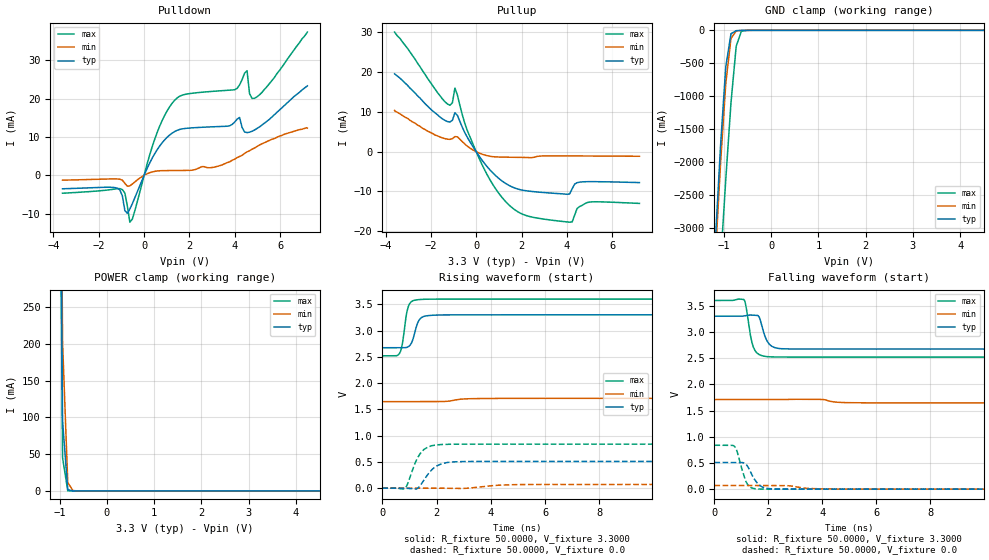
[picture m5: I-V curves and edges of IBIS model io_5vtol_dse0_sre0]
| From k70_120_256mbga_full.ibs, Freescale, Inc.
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[Model]  io_5vtol_dse0_sre0
|   Model io_5vtol_dse0_sre0
| Library cells for typ/min/max conditions are connected as defined below:
|  pad - External Pad
|  ipp_do - Core Input
|  ipp_obe - Output Buffer Enable
|  esd_boost - vdd_s_3v
|  esd_bus - vdd_s_3v
|  ipp_ame - vss_s_lv
|  ipp_dse - vss_s_lv
|  ipp_ina40a_5vtol - NC
|  ipp_ina40b_5vtol - NC
|  ipp_ina_5vtol - NC
|  ipp_ina_mux_3v - NC
|  ipp_ind - NC
|  ipp_ind_3v - NC
|  ipp_pue - vss_s_lv
|  ipp_sre - vss_s_lv
|  tie_3v - vdd_s_3v
|  tie_hi - vdd_s_lv
|  vbuf_3v - vdd_s_3v
|  vdd_bulk_lv - vdd_s_lv
|  vdd_s_3v - vdd_s_3v
|  vdd_s_lv - vdd_s_lv
|  vss_bulk - vss_s_3v
|  vss_s_3v - vss_s_3v
|  vss_s_lv - vss_s_lv
| All other pins connected to ground
Model_type I/O
Polarity   Non-Inverting
Enable   Active-High
Vinl =   1.1550V
Vinh =   2.3100V
Vmeas =  1.6500V
Cref =   25.0000pF
Rref =   50.0000
Vref =   0.0V
C_comp   2.8049pF   2.7887pF   2.9184pF
[Temperature Range]   25.0000   0.1250k   -40.0000
[Voltage Range]   3.3000V   1.7100V   3.6000V
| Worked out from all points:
|   slope of the pulldown table from 0 to 0.495 V, typ, clamps not added: 83.9 ohm
|   slope of the pullup table from 0 to 0.495 V, typ, clamps not added: 129 ohm
|   GND clamp passes 1 mA (typ) near -0.58 V on its own axis
|   POWER clamp passes 1 mA (typ) near -0.79 V on its own axis
|   rising waveform, R_fixture 50.0000, V_fixture 3.3000: 20-80 % time 227ps typ, 495ps min, 184ps max; typ from 2.67 V to 3.3 V
|   rising waveform, R_fixture 50.0000, V_fixture 0.0: 20-80 % time 495ps typ, 853ps min, 421ps max; typ from 0 V to 0.509 V
|   falling waveform, R_fixture 50.0000, V_fixture 3.3000: 20-80 % time 261ps typ, 395ps min, 224ps max; typ from 3.3 V to 2.67 V
|   falling waveform, R_fixture 50.0000, V_fixture 0.0: 20-80 % time 356ps typ, 598ps min, 285ps max; typ from 0.509 V to 0 V
[Pulldown]
|Voltage   I(typ)   I(min)   I(max)
-3.6V     -3.51mA    -1.26mA    -4.66mA
-1.29V    -3.199mA   -941uA     -3.563mA
-960mV    -5.372mA   -1.272mA   -3.734mA
-850mV    -9.168mA   -2.085mA   -4.602mA
-630mV    -8.788mA   -2.751mA   -12.21mA
580mV     6.709mA    1.133mA    11.22mA
1.35V     11.41mA    1.251mA    19.56mA
4.21V     15.06mA    4.9mA      23.54mA
4.54V     11.12mA    6.1mA      27.24mA
4.65V     11.23mA    6.4mA      21.29mA
4.87V     11.8mA     7.1mA      20.05mA
7.2V      23.3mA     12.3mA     37.3mA
[Pullup]
|Voltage   I(typ)   I(min)   I(max)
-3.6V     19.6mA     10.4mA     30.1mA
-1.38V    7.89mA     3.29mA     12.58mA
-1.05V    7.911mA    3.26mA     12.3mA
-940mV    9.791mA    3.808mA    16.02mA
-500mV    4.763mA    1.923mA    7.069mA
270mV     -2.225mA   -643.7uA   -3.408mA
930mV     -6.397mA   -1.322mA   -9.943mA
1.7V      -9.133mA   -1.405mA   -14.6mA
4.12V     -10.63mA   -1.06mA    -17.73mA
4.34V     -8.156mA   -1.06mA    -16mA
4.89V     -7.539mA   -1.08mA    -12.8mA
7.2V      -7.77mA    -1.14mA    -13mA
[GND_clamp]
|Voltage   I(typ)   I(min)   I(max)
-3.6V     -39.79A    -39.79A    -41.16A
-1.18V    -3.193A    -3.444A    -4.927A
-1.07V    -1.746A    -2.021A    -3.54A
-960mV    -554.7mA   -808.1mA   -2.265A
-850mV    -51.43mA   -125.2mA   -1.104A
-740mV    -5.185mA   -9.147mA   -242.4mA
-630mV    -1.474mA   -1.195mA   -14.98mA
-520mV    -384.8uA   -298.7uA   -1.148mA
7.2V      0A         0A         0A
[POWER_clamp]
|Voltage   I(typ)   I(min)   I(max)
-3.6V     45.62A     45.23A     45.93A
-1.05V    987.4mA    1.121A     927.4mA
-940mV    95.32mA    202.8mA    45.29mA
-830mV    1.645mA    11.46mA    218.1uA
-720mV    22.84uA    474.3uA    919.1nA
-610mV    316.6nA    19.24uA    4.178nA
7.2V      0A         0A         0A
[Ramp]
| variable   typ   min   max
dV/dt_r  0.3054/0.4951n   41.9957m/0.8527n   0.5027/0.4214n
dV/dt_f  0.3761/0.2609n   37.9284m/0.3951n   0.6484/0.2238n
R_load = 50.0000
[Rising Waveform]
R_fixture= 50.0000
V_fixture= 3.3000
V_fixture_min= 1.7100
V_fixture_max= 3.6000
|time   V(typ)   V(min)   V(max)
0s        2.673V     1.647V     2.519V
634.4ps   2.673V     1.647V     2.567V
742.6ps   2.673V     1.647V     2.76V
871.8ps   2.676V     1.647V     3.26V
943.5ps   2.689V     1.647V     3.438V
1.083ns   2.772V     1.647V     3.554V
1.335ns   3.181V     1.647V     3.59V
1.526ns   3.269V     1.647V     3.595V
2.19ns    3.298V     1.648V     3.599V
20ns      3.3V       1.71V      3.6V
[Rising Waveform]
R_fixture= 50.0000
V_fixture= 0.0
V_fixture_min= 0.0
V_fixture_max= 0.0
|time   V(typ)   V(min)   V(max)
0s        1.227nV    111.1nV    934.1pV
813ps     -20.38uV   2.027uV    -12.84mV
916.7ps   -3.205mV   -1.881uV   64.05mV
1.228ns   -19.69mV   8.868uV    500.1mV
1.393ns   47.23mV    76.41uV    657.8mV
1.746ns   307.5mV    269.6uV    794.2mV
2.14ns    453.5mV    -984uV     829.6mV
2.852ns   505.1mV    -7.746mV   836.7mV
5.06ns    508.7mV    67.63mV    837.4mV
20ns      508.9mV    69.99mV    837.8mV
[Falling Waveform]
R_fixture= 50.0000
V_fixture= 3.3000
V_fixture_min= 1.7100
V_fixture_max= 3.6000
|time   V(typ)   V(min)   V(max)
0s        3.3V       1.71V      3.6V
1.091ns   3.304V     1.71V      3.619V
1.155ns   3.31V      1.71V      3.527V
1.336ns   3.322V     1.71V      2.928V
1.438ns   3.32V      1.71V      2.716V
1.658ns   3.286V     1.71V      2.568V
1.946ns   2.83V      1.71V      2.529V
2.227ns   2.701V     1.71V      2.522V
2.633ns   2.677V     1.711V     2.521V
20ns      2.673V     1.647V     2.519V
[Falling Waveform]
R_fixture= 50.0000
V_fixture= 0.0
V_fixture_min= 0.0
V_fixture_max= 0.0
|time   V(typ)   V(min)   V(max)
0s        509mV      70.01mV    838mV
753.1ps   509mV      70.01mV    810.7mV
842ps     508.8mV    70.01mV    715.3mV
1.17ns    474.4mV    70mV       143.5mV
1.301ns   367.7mV    70mV       46.27mV
1.546ns   142.6mV    70mV       6.11mV
1.873ns   22.86mV    69.98mV    1.023mV
2.398ns   1.287mV    70.09mV    487.2uV
4.55ns    221.8uV    1.579mV    290.7uV
20ns      62.85uV    14.83uV    94.9uV
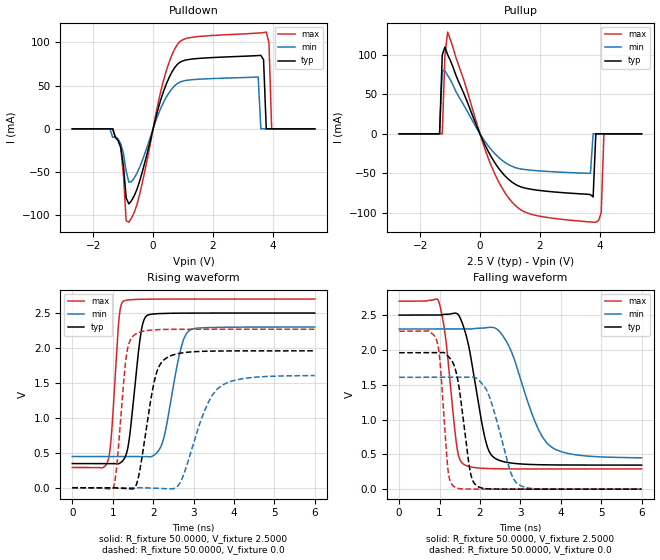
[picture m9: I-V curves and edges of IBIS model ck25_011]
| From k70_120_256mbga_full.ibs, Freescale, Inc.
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|   Model ck25_011
[Model]  ck25_011
Model_type Output
Polarity   Non-Inverting
Enable   Active-High
Vmeas =  1.2500V
Cref =   5.0000pF
Rref =   50.0000
C_comp   2.8000pF   2.5000pF   3.3000pF
[Temperature Range]   25.0000   0.1250k   -40.0000
[Voltage Range]   2.5000V   2.3000V   2.7000V
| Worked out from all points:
|   slope of the pulldown table from 0 to 0.375 V, typ, clamps not added: 8.18 ohm
|   slope of the pullup table from 0 to 0.375 V, typ, clamps not added: 12.9 ohm
|   rising waveform, R_fixture 50.0000, V_fixture 2.5000: 20-80 % time 236ps typ, 355ps min, 157ps max; typ from 0.346 V to 2.5 V
|   rising waveform, R_fixture 50.0000, V_fixture 0.0: 20-80 % time 334ps typ, 591ps min, 199ps max; typ from 0 V to 1.96 V
|   falling waveform, R_fixture 50.0000, V_fixture 2.5000: 20-80 % time 390ps typ, 673ps min, 252ps max; typ from 2.5 V to 0.346 V
|   falling waveform, R_fixture 50.0000, V_fixture 0.0: 20-80 % time 268ps typ, 459ps min, 168ps max; typ from 1.96 V to 0 V
[Pulldown]
|Voltage   I(typ)   I(min)   I(max)
-2.7V     0A         0A         0A
-1.35V    0A         -10mA      0A
-1.08V    -21.44mA   -17.23mA   -22.4mA
-810mV    -87.03mA   -61.88mA   -108.1mA
900mV     77.14mA    54.19mA    101.1mA
3.51V     84.84mA    60mA       110.9mA
3.6V      85mA       0A         111.1mA
3.69V     80mA       0A         111.4mA
3.78V     0A         0A         112mA
3.87V     0A         0A         100mA
3.96V     0A         0A         0A
5.4V      0A         0A         0A
[Pullup]
|Voltage   I(typ)   I(min)   I(max)
-2.7V     0A         0A         0A
-1.35V    0A         0A         0A
-1.26V    100mA      80mA       0A
-1.08V    100.4mA    74.2mA     129mA
1.44V     -68.08mA   -44.94mA   -97.96mA
3.69V     -77mA      -50mA      -111.7mA
3.78V     -80mA      0A         -112mA
3.87V     0A         0A         -112mA
3.96V     0A         0A         -110mA
4.05V     0A         0A         -100mA
4.14V     0A         0A         0A
5.4V      0A         0A         0A
[Ramp]
| variable   typ   min   max
dV/dt_r  1.1755/0.3339n   0.9631/0.5879n   1.3611/0.1989n
dV/dt_f  1.2925/0.3904n   1.1099/0.6692n   1.4460/0.2523n
R_load = 50.0000
[Rising Waveform]
R_fixture= 50.0000
V_fixture= 2.5000
V_fixture_min= 2.3000
V_fixture_max= 2.7000
|time   V(typ)   V(min)   V(max)
0s        345.9mV    446.9mV    289.9mV
885.9ps   345.8mV    446.9mV    390.1mV
1.154ns   345.3mV    446.9mV    2.407V
1.267ns   398.2mV    446.9mV    2.67V
1.405ns   677.7mV    446.9mV    2.689V
1.701ns   2.223V     446.9mV    2.697V
1.842ns   2.461V     446.4mV    2.698V
2.234ns   2.494V     652mV      2.7V
2.889ns   2.499V     2.248V     2.7V
6ns       2.5V       2.3V       2.7V
[Rising Waveform]
R_fixture= 50.0000
V_fixture= 0.0
|time   V(typ)   V(min)   V(max)
0s        3.819nV    263.8nV    1.818nV
1.021ns   292.5uV    252nV      11.35mV
1.341ns   -13.78mV   371.2nV    1.897V
1.571ns   25.49mV    -4.817uV   2.2V
2.035ns   1.538V     -6.959mV   2.26V
2.292ns   1.842V     -13.99mV   2.265V
2.657ns   1.924V     61.22mV    2.268V
3.284ns   1.953V     1.115V     2.268V
3.681ns   1.957V     1.456V     2.268V
6ns       1.959V     1.605V     2.268V
[Falling Waveform]
R_fixture= 50.0000
V_fixture= 2.5000
V_fixture_min= 2.3000
V_fixture_max= 2.7000
|time   V(typ)   V(min)   V(max)
0s        2.5V       2.3V       2.7V
976.9ps   2.5V       2.3V       2.699V
1.145ns   2.512V     2.3V       2.193V
1.436ns   2.521V     2.3V       576.7mV
1.591ns   2.337V     2.3V       359.2mV
2.107ns   775.2mV    2.316V     298.3mV
2.337ns   458.1mV    2.321V     293.7mV
2.722ns   379.2mV    2.046V     291mV
3.764ns   348.4mV    606mV      290mV
6ns       345.9mV    450.2mV    289.9mV
[Falling Waveform]
R_fixture= 50.0000
V_fixture= 0.0
|time   V(typ)   V(min)   V(max)
0s        1.959V     1.607V     2.268V
926.7ps   1.959V     1.607V     2.138V
1.013ns   1.959V     1.607V     1.817V
1.211ns   1.909V     1.607V     263.9mV
1.375ns   1.751V     1.607V     30.09mV
1.76ns    246.3mV    1.607V     1.635mV
1.938ns   41.96mV    1.582V     873.9uV
2.2ns     4.538mV    1.378V     347.6uV
2.965ns   505.8uV    62.98mV    24.95uV
6ns       457.6nV    38.86uV    9.273nV
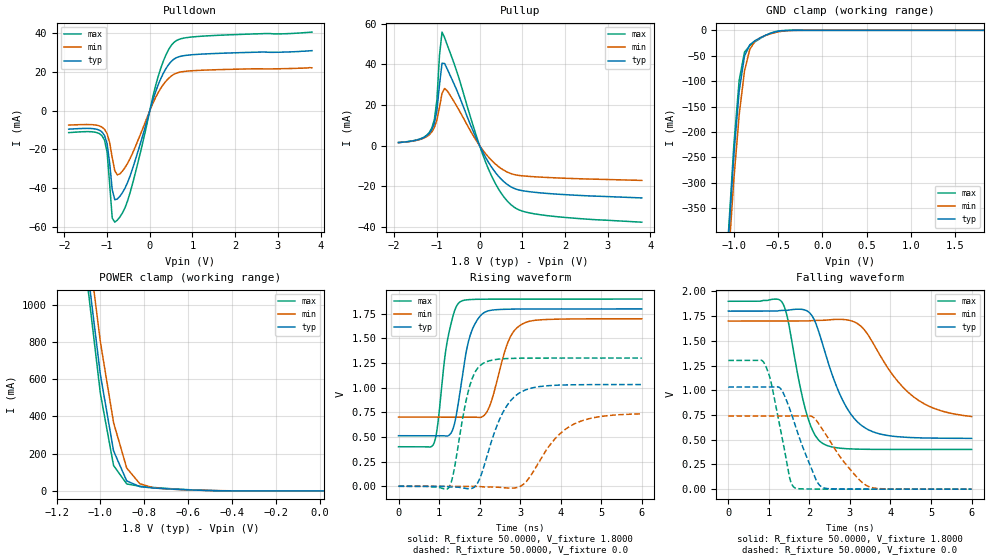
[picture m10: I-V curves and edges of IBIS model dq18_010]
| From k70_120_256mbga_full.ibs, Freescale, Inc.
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|   Model dq18_010
[Model]  dq18_010
Model_type 3-state
Polarity   Non-Inverting
Enable   Active-High
Vmeas =  0.9000V
Cref =   5.0000pF
Rref =   50.0000
C_comp   2.8000pF   2.5000pF   3.3000pF
[Temperature Range]   25.0000   0.1250k   -40.0000
[Voltage Range]   1.8000V   1.7000V   1.9000V
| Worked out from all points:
|   slope of the pulldown table from 0 to 0.27 V, typ, clamps not added: 15.7 ohm
|   slope of the pullup table from 0 to 0.27 V, typ, clamps not added: 26.3 ohm
|   GND clamp passes 1 mA (typ) near -0.46 V on its own axis
|   POWER clamp passes 1 mA (typ) near -0.45 V on its own axis
|   rising waveform, R_fixture 50.0000, V_fixture 1.8000: 20-80 % time 330ps typ, 419ps min, 277ps max; typ from 0.513 V to 1.8 V
|   rising waveform, R_fixture 50.0000, V_fixture 0.0: 20-80 % time 574ps typ, 828ps min, 362ps max; typ from 0 V to 1.03 V
|   falling waveform, R_fixture 50.0000, V_fixture 1.8000: 20-80 % time 732ps typ, 1.06ns min, 455ps max; typ from 1.8 V to 0.514 V
|   falling waveform, R_fixture 50.0000, V_fixture 0.0: 20-80 % time 548ps typ, 770ps min, 369ps max; typ from 1.03 V to 0 V
[Pulldown]
|Voltage   I(typ)   I(min)   I(max)
-1.9V     -9.546mA   -7.415mA   -11.34mA
-1.24V    -9.613mA   -7.507mA   -11.32mA
-1.06V    -12.84mA   -9.622mA   -15.29mA
-1V       -17.1mA    -11.9mA    -21.47mA
-880mV    -40.92mA   -24.25mA   -55.54mA
-820mV    -46.05mA   -31.1mA    -57.7mA
-700mV    -44.27mA   -32.63mA   -54.99mA
-520mV    -37.14mA   -27.24mA   -46.65mA
200mV     13.59mA    9.515mA    17.98mA
380mV     21.87mA    15.33mA    28.97mA
560mV     26.62mA    18.78mA    35.26mA
3.8V      31.1mA     22.2mA     40.7mA
[Pullup]
|Voltage   I(typ)   I(min)   I(max)
-1.9V     1.5mA      1.4mA      1.5mA
-1.36V    3.45mA     3.23mA     3.57mA
-1.12V    7.79mA     6.69mA     8.6mA
-1.06V    10.98mA    8.87mA     12.76mA
-1V       17.34mA    12.56mA    22.4mA
-940mV    29.86mA    18.76mA    44.29mA
-880mV    40.52mA    25.74mA    55.8mA
-760mV    37.72mA    26.99mA    49.56mA
140mV     -5.745mA   -3.949mA   -8.077mA
680mV     -19.58mA   -13.32mA   -27.96mA
1.4V      -23.19mA   -15.47mA   -33.93mA
3.8V      -25.74mA   -17.13mA   -37.67mA
[GND_clamp]
|Voltage   I(typ)   I(min)   I(max)
-1.9V     -3.325A    -3.292A    -3.364A
-1.06V    -406.4mA   -447.3mA   -394.5mA
-1V       -245mA     -292.8mA   -225.3mA
-940mV    -119.3mA   -166mA     -98.1mA
-880mV    -50.41mA   -79.82mA   -43mA
-820mV    -28.32mA   -37.2mA    -29.79mA
-760mV    -20.22mA   -21.27mA   -22.3mA
-700mV    -14.45mA   -14.4mA    -15.61mA
-580mV    -5.537mA   -6.461mA   -5.052mA
-460mV    -1.017mA   -1.864mA   -601.9uA
-220mV    -979.5nA   -15.35uA   -59.46nA
1.82V     915.2pA    951.9nA    210.6pA
[POWER_clamp]
|Voltage   I(typ)   I(min)   I(max)
-1.9V     11.94A     11.89A     12.02A
-1.06V    1.204A     1.363A     1.122A
-1V       623.7mA    800mA      522.5mA
-940mV    215.1mA    367.1mA    136.6mA
-880mV    53.67mA    122.9mA    37.6mA
-820mV    23.13mA    38.48mA    24.96mA
-760mV    15.75mA    17.21mA    18.82mA
-640mV    7.758mA    7.284mA    9.105mA
-460mV    1.139mA    1.585mA    966.7uA
20mV      398.7pA    26.73nA    225pA
[Ramp]
| variable   typ   min   max
dV/dt_r  0.6195/0.5740n   0.4409/0.8279n   0.7809/0.3617n
dV/dt_f  0.7718/0.7324n   0.5791/1.0609n   0.8992/0.4549n
R_load = 50.0000
[Rising Waveform]
R_fixture= 50.0000
V_fixture= 1.8000
V_fixture_min= 1.7000
V_fixture_max= 1.9000
|time   V(typ)   V(min)   V(max)
0s        513.2mV    702.3mV    401.3mV
877.5ps   513.2mV    702.3mV    439.1mV
1.201ns   509.8mV    702.3mV    1.47V
1.371ns   618.6mV    702.3mV    1.767V
1.526ns   985.4mV    702.3mV    1.874V
1.771ns   1.535V     702.6mV    1.895V
2.158ns   1.772V     741.6mV    1.899V
2.71ns    1.797V     1.473V     1.9V
3.036ns   1.799V     1.643V     1.9V
6ns       1.8V       1.7V       1.9V
[Rising Waveform]
R_fixture= 50.0000
V_fixture= 0.0
|time   V(typ)   V(min)   V(max)
0s        6.321nV    674nV      1.735nV
1.245ns   -6.519mV   1.112uV    -11.02mV
1.361ns   -6.931mV   744.8nV    142.9mV
1.753ns   -24.56mV   94.32uV    1.014V
1.939ns   24.72mV    -501.5uV   1.191V
2.125ns   224.5mV    -7.489mV   1.256V
2.545ns   726.3mV    -12.84mV   1.293V
3.039ns   960.3mV    7.994mV    1.3V
4.263ns   1.03V      617.3mV    1.302V
6ns       1.032V     734.8mV    1.302V
[Falling Waveform]
R_fixture= 50.0000
V_fixture= 1.8000
V_fixture_min= 1.7000
V_fixture_max= 1.9000
|time   V(typ)   V(min)   V(max)
0s        1.8V       1.7V       1.9V
1.327ns   1.808V     1.7V       1.89V
1.463ns   1.808V     1.7V       1.727V
1.756ns   1.82V      1.7V       1.066V
1.962ns   1.797V     1.7V       719.6mV
2.348ns   1.433V     1.707V     457.2mV
2.823ns   896.7mV    1.716V     411.9mV
3.373ns   619.3mV    1.602V     403.2mV
4.573ns   520.8mV    932.3mV    401.4mV
6ns       513.6mV    734.9mV    401.3mV
[Falling Waveform]
R_fixture= 50.0000
V_fixture= 0.0
|time   V(typ)   V(min)   V(max)
0s        1.032V     739.4mV    1.302V
900.9ps   1.033V     739.4mV    1.264V
1.049ns   1.032V     739.4mV    1.089V
1.293ns   1.016V     739.4mV    592.4mV
1.51ns    817mV      739.4mV    118.8mV
1.634ns   664.4mV    739.4mV    14.99mV
2.065ns   191.6mV    734.7mV    1.166mV
2.339ns   14.86mV    594.5mV    462.2uV
3.454ns   315.6uV    27.78mV    14.19uV
6ns       1.891uV    73.85uV    90.84nV
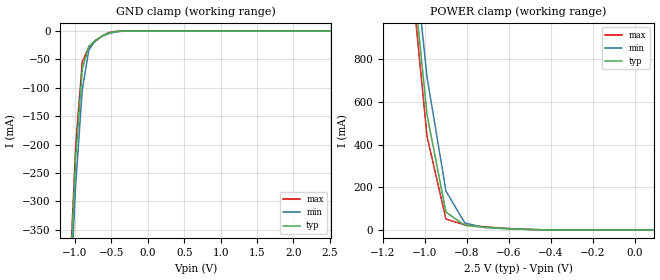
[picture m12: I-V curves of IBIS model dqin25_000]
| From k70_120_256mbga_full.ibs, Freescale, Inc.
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|   Model dqin25_000
[Model]  dqin25_000
Model_type Input
Polarity   Non-Inverting
Enable   Active-High
Vinl =   0.9400V
Vinh =   1.5600V
C_comp   2.8000pF   2.5000pF   3.3000pF
[Temperature Range]   25.0000   0.1250k   -40.0000
[Voltage Range]   2.5000V   2.3000V   2.7000V
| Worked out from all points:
|   GND clamp passes 1 mA (typ) near -0.45 V on its own axis
|   POWER clamp passes 1 mA (typ) near -0.45 V on its own axis
[GND_clamp]
|Voltage   I(typ)   I(min)   I(max)
-2.7V     -6.278A    -6.223A    -6.333A
-1.08V    -465.3mA   -503.1mA   -456mA
-990mV    -221.1mA   -269.5mA   -200.5mA
-900mV    -66.71mA   -103.5mA   -53.76mA
-810mV    -26.68mA   -33.38mA   -28.58mA
-720mV    -16.34mA   -16.32mA   -17.87mA
-630mV    -8.846mA   -9.35mA    -8.908mA
-540mV    -3.521mA   -4.589mA   -2.875mA
-450mV    -853.3uA   -1.64mA    -486.8uA
-270mV    -5.965uA   -53.73uA   -641.6nA
2.52V     1.058nA    13.31uA    283.6pA
[POWER_clamp]
|Voltage   I(typ)   I(min)   I(max)
-2.7V     22.73A     22.6A      22.86A
-1.08V    1.419A     1.569A     1.345A
-990mV    540.5mA    717mA      438.5mA
-900mV    83.91mA    182.3mA    51.06mA
-810mV    21.4mA     32.65mA    23.87mA
-720mV    12.71mA    12.3mA     15.28mA
-450mV    963.3uA    1.41mA     776.5uA
90mV      406pA      14.8nA     304.6pA
